VERSION 5.7 ;
BUSBITCHARS "[]" ;
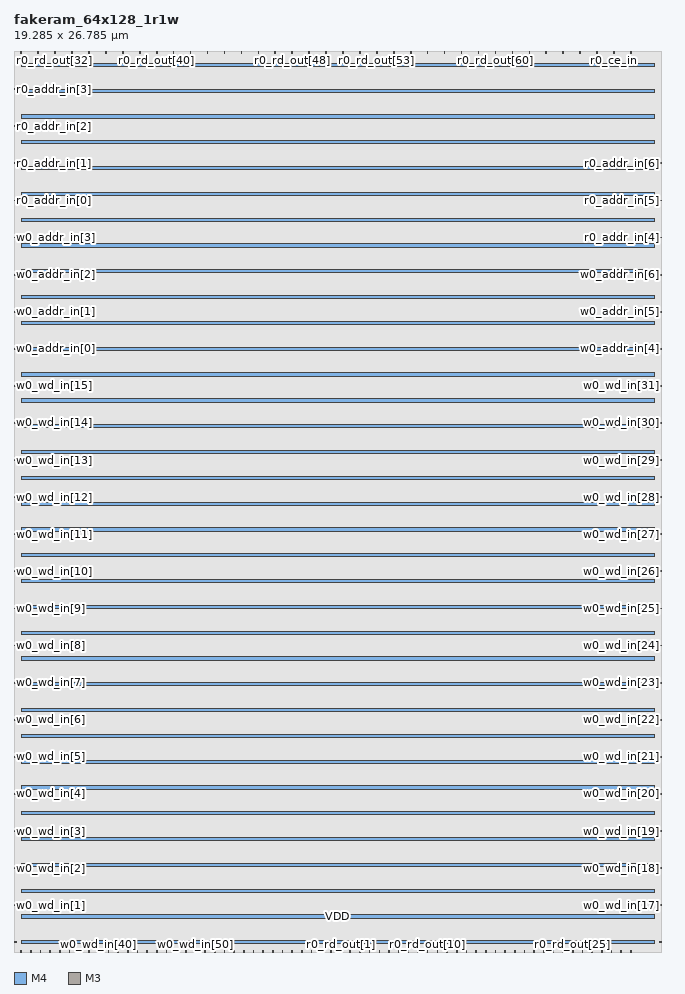
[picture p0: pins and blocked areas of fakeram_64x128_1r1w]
MACRO fakeram_64x128_1r1w
  FOREIGN fakeram_64x128_1r1w 0 0 ;
  SYMMETRY X Y R90 ;
  SIZE 19.285 BY 26.785 ;
  CLASS BLOCK ;
  PIN w0_wd_in[0]
    DIRECTION INPUT ;
    USE SIGNAL ;
    SHAPE ABUTMENT ;
    PORT
      LAYER M4 ;
      RECT 0.000 0.276 0.072 0.300 ;
    END
  END w0_wd_in[0]
  PIN w0_wd_in[1]
    DIRECTION INPUT ;
    USE SIGNAL ;
    SHAPE ABUTMENT ;
    PORT
      LAYER M4 ;
      RECT 0.000 1.380 0.072 1.404 ;
    END
  END w0_wd_in[1]
  PIN w0_wd_in[2]
    DIRECTION INPUT ;
    USE SIGNAL ;
    SHAPE ABUTMENT ;
    PORT
      LAYER M4 ;
      RECT 0.000 2.484 0.072 2.508 ;
    END
  END w0_wd_in[2]
  PIN w0_wd_in[3]
    DIRECTION INPUT ;
    USE SIGNAL ;
    SHAPE ABUTMENT ;
    PORT
      LAYER M4 ;
      RECT 0.000 3.588 0.072 3.612 ;
    END
  END w0_wd_in[3]
  PIN w0_wd_in[4]
    DIRECTION INPUT ;
    USE SIGNAL ;
    SHAPE ABUTMENT ;
    PORT
      LAYER M4 ;
      RECT 0.000 4.692 0.072 4.716 ;
    END
  END w0_wd_in[4]
  PIN w0_wd_in[5]
    DIRECTION INPUT ;
    USE SIGNAL ;
    SHAPE ABUTMENT ;
    PORT
      LAYER M4 ;
      RECT 0.000 5.796 0.072 5.820 ;
    END
  END w0_wd_in[5]
  PIN w0_wd_in[6]
    DIRECTION INPUT ;
    USE SIGNAL ;
    SHAPE ABUTMENT ;
    PORT
      LAYER M4 ;
      RECT 0.000 6.900 0.072 6.924 ;
    END
  END w0_wd_in[6]
  PIN w0_wd_in[7]
    DIRECTION INPUT ;
    USE SIGNAL ;
    SHAPE ABUTMENT ;
    PORT
      LAYER M4 ;
      RECT 0.000 8.004 0.072 8.028 ;
    END
  END w0_wd_in[7]
  PIN w0_wd_in[8]
    DIRECTION INPUT ;
    USE SIGNAL ;
    SHAPE ABUTMENT ;
    PORT
      LAYER M4 ;
      RECT 0.000 9.108 0.072 9.132 ;
    END
  END w0_wd_in[8]
  PIN w0_wd_in[9]
    DIRECTION INPUT ;
    USE SIGNAL ;
    SHAPE ABUTMENT ;
    PORT
      LAYER M4 ;
      RECT 0.000 10.212 0.072 10.236 ;
    END
  END w0_wd_in[9]
  PIN w0_wd_in[10]
    DIRECTION INPUT ;
    USE SIGNAL ;
    SHAPE ABUTMENT ;
    PORT
      LAYER M4 ;
      RECT 0.000 11.316 0.072 11.340 ;
    END
  END w0_wd_in[10]
  PIN w0_wd_in[11]
    DIRECTION INPUT ;
    USE SIGNAL ;
    SHAPE ABUTMENT ;
    PORT
      LAYER M4 ;
      RECT 0.000 12.420 0.072 12.444 ;
    END
  END w0_wd_in[11]
  PIN w0_wd_in[12]
    DIRECTION INPUT ;
    USE SIGNAL ;
    SHAPE ABUTMENT ;
    PORT
      LAYER M4 ;
      RECT 0.000 13.524 0.072 13.548 ;
    END
  END w0_wd_in[12]
  PIN w0_wd_in[13]
    DIRECTION INPUT ;
    USE SIGNAL ;
    SHAPE ABUTMENT ;
    PORT
      LAYER M4 ;
      RECT 0.000 14.628 0.072 14.652 ;
    END
  END w0_wd_in[13]
  PIN w0_wd_in[14]
    DIRECTION INPUT ;
    USE SIGNAL ;
    SHAPE ABUTMENT ;
    PORT
      LAYER M4 ;
      RECT 0.000 15.732 0.072 15.756 ;
    END
  END w0_wd_in[14]
  PIN w0_wd_in[15]
    DIRECTION INPUT ;
    USE SIGNAL ;
    SHAPE ABUTMENT ;
    PORT
      LAYER M4 ;
      RECT 0.000 16.836 0.072 16.860 ;
    END
  END w0_wd_in[15]
  PIN w0_wd_in[16]
    DIRECTION INPUT ;
    USE SIGNAL ;
    SHAPE ABUTMENT ;
    PORT
      LAYER M4 ;
      RECT 19.213 0.276 19.285 0.300 ;
    END
  END w0_wd_in[16]
  PIN w0_wd_in[17]
    DIRECTION INPUT ;
    USE SIGNAL ;
    SHAPE ABUTMENT ;
    PORT
      LAYER M4 ;
      RECT 19.213 1.380 19.285 1.404 ;
    END
  END w0_wd_in[17]
  PIN w0_wd_in[18]
    DIRECTION INPUT ;
    USE SIGNAL ;
    SHAPE ABUTMENT ;
    PORT
      LAYER M4 ;
      RECT 19.213 2.484 19.285 2.508 ;
    END
  END w0_wd_in[18]
  PIN w0_wd_in[19]
    DIRECTION INPUT ;
    USE SIGNAL ;
    SHAPE ABUTMENT ;
    PORT
      LAYER M4 ;
      RECT 19.213 3.588 19.285 3.612 ;
    END
  END w0_wd_in[19]
  PIN w0_wd_in[20]
    DIRECTION INPUT ;
    USE SIGNAL ;
    SHAPE ABUTMENT ;
    PORT
      LAYER M4 ;
      RECT 19.213 4.692 19.285 4.716 ;
    END
  END w0_wd_in[20]
  PIN w0_wd_in[21]
    DIRECTION INPUT ;
    USE SIGNAL ;
    SHAPE ABUTMENT ;
    PORT
      LAYER M4 ;
      RECT 19.213 5.796 19.285 5.820 ;
    END
  END w0_wd_in[21]
  PIN w0_wd_in[22]
    DIRECTION INPUT ;
    USE SIGNAL ;
    SHAPE ABUTMENT ;
    PORT
      LAYER M4 ;
      RECT 19.213 6.900 19.285 6.924 ;
    END
  END w0_wd_in[22]
  PIN w0_wd_in[23]
    DIRECTION INPUT ;
    USE SIGNAL ;
    SHAPE ABUTMENT ;
    PORT
      LAYER M4 ;
      RECT 19.213 8.004 19.285 8.028 ;
    END
  END w0_wd_in[23]
  PIN w0_wd_in[24]
    DIRECTION INPUT ;
    USE SIGNAL ;
    SHAPE ABUTMENT ;
    PORT
      LAYER M4 ;
      RECT 19.213 9.108 19.285 9.132 ;
    END
  END w0_wd_in[24]
  PIN w0_wd_in[25]
    DIRECTION INPUT ;
    USE SIGNAL ;
    SHAPE ABUTMENT ;
    PORT
      LAYER M4 ;
      RECT 19.213 10.212 19.285 10.236 ;
    END
  END w0_wd_in[25]
  PIN w0_wd_in[26]
    DIRECTION INPUT ;
    USE SIGNAL ;
    SHAPE ABUTMENT ;
    PORT
      LAYER M4 ;
      RECT 19.213 11.316 19.285 11.340 ;
    END
  END w0_wd_in[26]
  PIN w0_wd_in[27]
    DIRECTION INPUT ;
    USE SIGNAL ;
    SHAPE ABUTMENT ;
    PORT
      LAYER M4 ;
      RECT 19.213 12.420 19.285 12.444 ;
    END
  END w0_wd_in[27]
  PIN w0_wd_in[28]
    DIRECTION INPUT ;
    USE SIGNAL ;
    SHAPE ABUTMENT ;
    PORT
      LAYER M4 ;
      RECT 19.213 13.524 19.285 13.548 ;
    END
  END w0_wd_in[28]
  PIN w0_wd_in[29]
    DIRECTION INPUT ;
    USE SIGNAL ;
    SHAPE ABUTMENT ;
    PORT
      LAYER M4 ;
      RECT 19.213 14.628 19.285 14.652 ;
    END
  END w0_wd_in[29]
  PIN w0_wd_in[30]
    DIRECTION INPUT ;
    USE SIGNAL ;
    SHAPE ABUTMENT ;
    PORT
      LAYER M4 ;
      RECT 19.213 15.732 19.285 15.756 ;
    END
  END w0_wd_in[30]
  PIN w0_wd_in[31]
    DIRECTION INPUT ;
    USE SIGNAL ;
    SHAPE ABUTMENT ;
    PORT
      LAYER M4 ;
      RECT 19.213 16.836 19.285 16.860 ;
    END
  END w0_wd_in[31]
  PIN w0_wd_in[32]
    DIRECTION OUTPUT ;
    USE SIGNAL ;
    SHAPE ABUTMENT ;
    PORT
      LAYER M3 ;
      RECT 0.207 0.000 0.225 0.054 ;
    END
  END w0_wd_in[32]
  PIN w0_wd_in[33]
    DIRECTION OUTPUT ;
    USE SIGNAL ;
    SHAPE ABUTMENT ;
    PORT
      LAYER M3 ;
      RECT 0.495 0.000 0.513 0.054 ;
    END
  END w0_wd_in[33]
  PIN w0_wd_in[34]
    DIRECTION OUTPUT ;
    USE SIGNAL ;
    SHAPE ABUTMENT ;
    PORT
      LAYER M3 ;
      RECT 0.783 0.000 0.801 0.054 ;
    END
  END w0_wd_in[34]
  PIN w0_wd_in[35]
    DIRECTION OUTPUT ;
    USE SIGNAL ;
    SHAPE ABUTMENT ;
    PORT
      LAYER M3 ;
      RECT 1.071 0.000 1.089 0.054 ;
    END
  END w0_wd_in[35]
  PIN w0_wd_in[36]
    DIRECTION OUTPUT ;
    USE SIGNAL ;
    SHAPE ABUTMENT ;
    PORT
      LAYER M3 ;
      RECT 1.359 0.000 1.377 0.054 ;
    END
  END w0_wd_in[36]
  PIN w0_wd_in[37]
    DIRECTION OUTPUT ;
    USE SIGNAL ;
    SHAPE ABUTMENT ;
    PORT
      LAYER M3 ;
      RECT 1.647 0.000 1.665 0.054 ;
    END
  END w0_wd_in[37]
  PIN w0_wd_in[38]
    DIRECTION OUTPUT ;
    USE SIGNAL ;
    SHAPE ABUTMENT ;
    PORT
      LAYER M3 ;
      RECT 1.935 0.000 1.953 0.054 ;
    END
  END w0_wd_in[38]
  PIN w0_wd_in[39]
    DIRECTION OUTPUT ;
    USE SIGNAL ;
    SHAPE ABUTMENT ;
    PORT
      LAYER M3 ;
      RECT 2.223 0.000 2.241 0.054 ;
    END
  END w0_wd_in[39]
  PIN w0_wd_in[40]
    DIRECTION OUTPUT ;
    USE SIGNAL ;
    SHAPE ABUTMENT ;
    PORT
      LAYER M3 ;
      RECT 2.511 0.000 2.529 0.054 ;
    END
  END w0_wd_in[40]
  PIN w0_wd_in[41]
    DIRECTION OUTPUT ;
    USE SIGNAL ;
    SHAPE ABUTMENT ;
    PORT
      LAYER M3 ;
      RECT 2.799 0.000 2.817 0.054 ;
    END
  END w0_wd_in[41]
  PIN w0_wd_in[42]
    DIRECTION OUTPUT ;
    USE SIGNAL ;
    SHAPE ABUTMENT ;
    PORT
      LAYER M3 ;
      RECT 3.087 0.000 3.105 0.054 ;
    END
  END w0_wd_in[42]
  PIN w0_wd_in[43]
    DIRECTION OUTPUT ;
    USE SIGNAL ;
    SHAPE ABUTMENT ;
    PORT
      LAYER M3 ;
      RECT 3.375 0.000 3.393 0.054 ;
    END
  END w0_wd_in[43]
  PIN w0_wd_in[44]
    DIRECTION OUTPUT ;
    USE SIGNAL ;
    SHAPE ABUTMENT ;
    PORT
      LAYER M3 ;
      RECT 3.663 0.000 3.681 0.054 ;
    END
  END w0_wd_in[44]
  PIN w0_wd_in[45]
    DIRECTION OUTPUT ;
    USE SIGNAL ;
    SHAPE ABUTMENT ;
    PORT
      LAYER M3 ;
      RECT 3.951 0.000 3.969 0.054 ;
    END
  END w0_wd_in[45]
  PIN w0_wd_in[46]
    DIRECTION OUTPUT ;
    USE SIGNAL ;
    SHAPE ABUTMENT ;
    PORT
      LAYER M3 ;
      RECT 4.239 0.000 4.257 0.054 ;
    END
  END w0_wd_in[46]
  PIN w0_wd_in[47]
    DIRECTION OUTPUT ;
    USE SIGNAL ;
    SHAPE ABUTMENT ;
    PORT
      LAYER M3 ;
      RECT 4.527 0.000 4.545 0.054 ;
    END
  END w0_wd_in[47]
  PIN w0_wd_in[48]
    DIRECTION OUTPUT ;
    USE SIGNAL ;
    SHAPE ABUTMENT ;
    PORT
      LAYER M3 ;
      RECT 4.815 0.000 4.833 0.054 ;
    END
  END w0_wd_in[48]
  PIN w0_wd_in[49]
    DIRECTION OUTPUT ;
    USE SIGNAL ;
    SHAPE ABUTMENT ;
    PORT
      LAYER M3 ;
      RECT 5.103 0.000 5.121 0.054 ;
    END
  END w0_wd_in[49]
  PIN w0_wd_in[50]
    DIRECTION OUTPUT ;
    USE SIGNAL ;
    SHAPE ABUTMENT ;
    PORT
      LAYER M3 ;
      RECT 5.391 0.000 5.409 0.054 ;
    END
  END w0_wd_in[50]
  PIN w0_wd_in[51]
    DIRECTION OUTPUT ;
    USE SIGNAL ;
    SHAPE ABUTMENT ;
    PORT
      LAYER M3 ;
      RECT 5.679 0.000 5.697 0.054 ;
    END
  END w0_wd_in[51]
  PIN w0_wd_in[52]
    DIRECTION OUTPUT ;
    USE SIGNAL ;
    SHAPE ABUTMENT ;
    PORT
      LAYER M3 ;
      RECT 5.967 0.000 5.985 0.054 ;
    END
  END w0_wd_in[52]
  PIN w0_wd_in[53]
    DIRECTION OUTPUT ;
    USE SIGNAL ;
    SHAPE ABUTMENT ;
    PORT
      LAYER M3 ;
      RECT 6.255 0.000 6.273 0.054 ;
    END
  END w0_wd_in[53]
  PIN w0_wd_in[54]
    DIRECTION OUTPUT ;
    USE SIGNAL ;
    SHAPE ABUTMENT ;
    PORT
      LAYER M3 ;
      RECT 6.543 0.000 6.561 0.054 ;
    END
  END w0_wd_in[54]
  PIN w0_wd_in[55]
    DIRECTION OUTPUT ;
    USE SIGNAL ;
    SHAPE ABUTMENT ;
    PORT
      LAYER M3 ;
      RECT 6.831 0.000 6.849 0.054 ;
    END
  END w0_wd_in[55]
  PIN w0_wd_in[56]
    DIRECTION OUTPUT ;
    USE SIGNAL ;
    SHAPE ABUTMENT ;
    PORT
      LAYER M3 ;
      RECT 7.119 0.000 7.137 0.054 ;
    END
  END w0_wd_in[56]
  PIN w0_wd_in[57]
    DIRECTION OUTPUT ;
    USE SIGNAL ;
    SHAPE ABUTMENT ;
    PORT
      LAYER M3 ;
      RECT 7.407 0.000 7.425 0.054 ;
    END
  END w0_wd_in[57]
  PIN w0_wd_in[58]
    DIRECTION OUTPUT ;
    USE SIGNAL ;
    SHAPE ABUTMENT ;
    PORT
      LAYER M3 ;
      RECT 7.695 0.000 7.713 0.054 ;
    END
  END w0_wd_in[58]
  PIN w0_wd_in[59]
    DIRECTION OUTPUT ;
    USE SIGNAL ;
    SHAPE ABUTMENT ;
    PORT
      LAYER M3 ;
      RECT 7.983 0.000 8.001 0.054 ;
    END
  END w0_wd_in[59]
  PIN w0_wd_in[60]
    DIRECTION OUTPUT ;
    USE SIGNAL ;
    SHAPE ABUTMENT ;
    PORT
      LAYER M3 ;
      RECT 8.271 0.000 8.289 0.054 ;
    END
  END w0_wd_in[60]
  PIN w0_wd_in[61]
    DIRECTION OUTPUT ;
    USE SIGNAL ;
    SHAPE ABUTMENT ;
    PORT
      LAYER M3 ;
      RECT 8.559 0.000 8.577 0.054 ;
    END
  END w0_wd_in[61]
  PIN w0_wd_in[62]
    DIRECTION OUTPUT ;
    USE SIGNAL ;
    SHAPE ABUTMENT ;
    PORT
      LAYER M3 ;
      RECT 8.847 0.000 8.865 0.054 ;
    END
  END w0_wd_in[62]
  PIN w0_wd_in[63]
    DIRECTION OUTPUT ;
    USE SIGNAL ;
    SHAPE ABUTMENT ;
    PORT
      LAYER M3 ;
      RECT 9.135 0.000 9.153 0.054 ;
    END
  END w0_wd_in[63]
  PIN r0_rd_out[0]
    DIRECTION OUTPUT ;
    USE SIGNAL ;
    SHAPE ABUTMENT ;
    PORT
      LAYER M3 ;
      RECT 9.423 0.000 9.441 0.054 ;
    END
  END r0_rd_out[0]
  PIN r0_rd_out[1]
    DIRECTION OUTPUT ;
    USE SIGNAL ;
    SHAPE ABUTMENT ;
    PORT
      LAYER M3 ;
      RECT 9.711 0.000 9.729 0.054 ;
    END
  END r0_rd_out[1]
  PIN r0_rd_out[2]
    DIRECTION OUTPUT ;
    USE SIGNAL ;
    SHAPE ABUTMENT ;
    PORT
      LAYER M3 ;
      RECT 9.999 0.000 10.017 0.054 ;
    END
  END r0_rd_out[2]
  PIN r0_rd_out[3]
    DIRECTION OUTPUT ;
    USE SIGNAL ;
    SHAPE ABUTMENT ;
    PORT
      LAYER M3 ;
      RECT 10.287 0.000 10.305 0.054 ;
    END
  END r0_rd_out[3]
  PIN r0_rd_out[4]
    DIRECTION OUTPUT ;
    USE SIGNAL ;
    SHAPE ABUTMENT ;
    PORT
      LAYER M3 ;
      RECT 10.575 0.000 10.593 0.054 ;
    END
  END r0_rd_out[4]
  PIN r0_rd_out[5]
    DIRECTION OUTPUT ;
    USE SIGNAL ;
    SHAPE ABUTMENT ;
    PORT
      LAYER M3 ;
      RECT 10.863 0.000 10.881 0.054 ;
    END
  END r0_rd_out[5]
  PIN r0_rd_out[6]
    DIRECTION OUTPUT ;
    USE SIGNAL ;
    SHAPE ABUTMENT ;
    PORT
      LAYER M3 ;
      RECT 11.151 0.000 11.169 0.054 ;
    END
  END r0_rd_out[6]
  PIN r0_rd_out[7]
    DIRECTION OUTPUT ;
    USE SIGNAL ;
    SHAPE ABUTMENT ;
    PORT
      LAYER M3 ;
      RECT 11.439 0.000 11.457 0.054 ;
    END
  END r0_rd_out[7]
  PIN r0_rd_out[8]
    DIRECTION OUTPUT ;
    USE SIGNAL ;
    SHAPE ABUTMENT ;
    PORT
      LAYER M3 ;
      RECT 11.727 0.000 11.745 0.054 ;
    END
  END r0_rd_out[8]
  PIN r0_rd_out[9]
    DIRECTION OUTPUT ;
    USE SIGNAL ;
    SHAPE ABUTMENT ;
    PORT
      LAYER M3 ;
      RECT 12.015 0.000 12.033 0.054 ;
    END
  END r0_rd_out[9]
  PIN r0_rd_out[10]
    DIRECTION OUTPUT ;
    USE SIGNAL ;
    SHAPE ABUTMENT ;
    PORT
      LAYER M3 ;
      RECT 12.303 0.000 12.321 0.054 ;
    END
  END r0_rd_out[10]
  PIN r0_rd_out[11]
    DIRECTION OUTPUT ;
    USE SIGNAL ;
    SHAPE ABUTMENT ;
    PORT
      LAYER M3 ;
      RECT 12.591 0.000 12.609 0.054 ;
    END
  END r0_rd_out[11]
  PIN r0_rd_out[12]
    DIRECTION OUTPUT ;
    USE SIGNAL ;
    SHAPE ABUTMENT ;
    PORT
      LAYER M3 ;
      RECT 12.879 0.000 12.897 0.054 ;
    END
  END r0_rd_out[12]
  PIN r0_rd_out[13]
    DIRECTION OUTPUT ;
    USE SIGNAL ;
    SHAPE ABUTMENT ;
    PORT
      LAYER M3 ;
      RECT 13.167 0.000 13.185 0.054 ;
    END
  END r0_rd_out[13]
  PIN r0_rd_out[14]
    DIRECTION OUTPUT ;
    USE SIGNAL ;
    SHAPE ABUTMENT ;
    PORT
      LAYER M3 ;
      RECT 13.455 0.000 13.473 0.054 ;
    END
  END r0_rd_out[14]
  PIN r0_rd_out[15]
    DIRECTION OUTPUT ;
    USE SIGNAL ;
    SHAPE ABUTMENT ;
    PORT
      LAYER M3 ;
      RECT 13.743 0.000 13.761 0.054 ;
    END
  END r0_rd_out[15]
  PIN r0_rd_out[16]
    DIRECTION OUTPUT ;
    USE SIGNAL ;
    SHAPE ABUTMENT ;
    PORT
      LAYER M3 ;
      RECT 14.031 0.000 14.049 0.054 ;
    END
  END r0_rd_out[16]
  PIN r0_rd_out[17]
    DIRECTION OUTPUT ;
    USE SIGNAL ;
    SHAPE ABUTMENT ;
    PORT
      LAYER M3 ;
      RECT 14.319 0.000 14.337 0.054 ;
    END
  END r0_rd_out[17]
  PIN r0_rd_out[18]
    DIRECTION OUTPUT ;
    USE SIGNAL ;
    SHAPE ABUTMENT ;
    PORT
      LAYER M3 ;
      RECT 14.607 0.000 14.625 0.054 ;
    END
  END r0_rd_out[18]
  PIN r0_rd_out[19]
    DIRECTION OUTPUT ;
    USE SIGNAL ;
    SHAPE ABUTMENT ;
    PORT
      LAYER M3 ;
      RECT 14.895 0.000 14.913 0.054 ;
    END
  END r0_rd_out[19]
  PIN r0_rd_out[20]
    DIRECTION OUTPUT ;
    USE SIGNAL ;
    SHAPE ABUTMENT ;
    PORT
      LAYER M3 ;
      RECT 15.183 0.000 15.201 0.054 ;
    END
  END r0_rd_out[20]
  PIN r0_rd_out[21]
    DIRECTION OUTPUT ;
    USE SIGNAL ;
    SHAPE ABUTMENT ;
    PORT
      LAYER M3 ;
      RECT 15.471 0.000 15.489 0.054 ;
    END
  END r0_rd_out[21]
  PIN r0_rd_out[22]
    DIRECTION OUTPUT ;
    USE SIGNAL ;
    SHAPE ABUTMENT ;
    PORT
      LAYER M3 ;
      RECT 15.759 0.000 15.777 0.054 ;
    END
  END r0_rd_out[22]
  PIN r0_rd_out[23]
    DIRECTION OUTPUT ;
    USE SIGNAL ;
    SHAPE ABUTMENT ;
    PORT
      LAYER M3 ;
      RECT 16.047 0.000 16.065 0.054 ;
    END
  END r0_rd_out[23]
  PIN r0_rd_out[24]
    DIRECTION OUTPUT ;
    USE SIGNAL ;
    SHAPE ABUTMENT ;
    PORT
      LAYER M3 ;
      RECT 16.335 0.000 16.353 0.054 ;
    END
  END r0_rd_out[24]
  PIN r0_rd_out[25]
    DIRECTION OUTPUT ;
    USE SIGNAL ;
    SHAPE ABUTMENT ;
    PORT
      LAYER M3 ;
      RECT 16.623 0.000 16.641 0.054 ;
    END
  END r0_rd_out[25]
  PIN r0_rd_out[26]
    DIRECTION OUTPUT ;
    USE SIGNAL ;
    SHAPE ABUTMENT ;
    PORT
      LAYER M3 ;
      RECT 16.911 0.000 16.929 0.054 ;
    END
  END r0_rd_out[26]
  PIN r0_rd_out[27]
    DIRECTION OUTPUT ;
    USE SIGNAL ;
    SHAPE ABUTMENT ;
    PORT
      LAYER M3 ;
      RECT 17.199 0.000 17.217 0.054 ;
    END
  END r0_rd_out[27]
  PIN r0_rd_out[28]
    DIRECTION OUTPUT ;
    USE SIGNAL ;
    SHAPE ABUTMENT ;
    PORT
      LAYER M3 ;
      RECT 17.487 0.000 17.505 0.054 ;
    END
  END r0_rd_out[28]
  PIN r0_rd_out[29]
    DIRECTION OUTPUT ;
    USE SIGNAL ;
    SHAPE ABUTMENT ;
    PORT
      LAYER M3 ;
      RECT 17.775 0.000 17.793 0.054 ;
    END
  END r0_rd_out[29]
  PIN r0_rd_out[30]
    DIRECTION OUTPUT ;
    USE SIGNAL ;
    SHAPE ABUTMENT ;
    PORT
      LAYER M3 ;
      RECT 18.063 0.000 18.081 0.054 ;
    END
  END r0_rd_out[30]
  PIN r0_rd_out[31]
    DIRECTION OUTPUT ;
    USE SIGNAL ;
    SHAPE ABUTMENT ;
    PORT
      LAYER M3 ;
      RECT 18.351 0.000 18.369 0.054 ;
    END
  END r0_rd_out[31]
  PIN r0_rd_out[32]
    DIRECTION OUTPUT ;
    USE SIGNAL ;
    SHAPE ABUTMENT ;
    PORT
      LAYER M3 ;
      RECT 0.207 26.731 0.225 26.785 ;
    END
  END r0_rd_out[32]
  PIN r0_rd_out[33]
    DIRECTION OUTPUT ;
    USE SIGNAL ;
    SHAPE ABUTMENT ;
    PORT
      LAYER M3 ;
      RECT 0.711 26.731 0.729 26.785 ;
    END
  END r0_rd_out[33]
  PIN r0_rd_out[34]
    DIRECTION OUTPUT ;
    USE SIGNAL ;
    SHAPE ABUTMENT ;
    PORT
      LAYER M3 ;
      RECT 1.215 26.731 1.233 26.785 ;
    END
  END r0_rd_out[34]
  PIN r0_rd_out[35]
    DIRECTION OUTPUT ;
    USE SIGNAL ;
    SHAPE ABUTMENT ;
    PORT
      LAYER M3 ;
      RECT 1.719 26.731 1.737 26.785 ;
    END
  END r0_rd_out[35]
  PIN r0_rd_out[36]
    DIRECTION OUTPUT ;
    USE SIGNAL ;
    SHAPE ABUTMENT ;
    PORT
      LAYER M3 ;
      RECT 2.223 26.731 2.241 26.785 ;
    END
  END r0_rd_out[36]
  PIN r0_rd_out[37]
    DIRECTION OUTPUT ;
    USE SIGNAL ;
    SHAPE ABUTMENT ;
    PORT
      LAYER M3 ;
      RECT 2.727 26.731 2.745 26.785 ;
    END
  END r0_rd_out[37]
  PIN r0_rd_out[38]
    DIRECTION OUTPUT ;
    USE SIGNAL ;
    SHAPE ABUTMENT ;
    PORT
      LAYER M3 ;
      RECT 3.231 26.731 3.249 26.785 ;
    END
  END r0_rd_out[38]
  PIN r0_rd_out[39]
    DIRECTION OUTPUT ;
    USE SIGNAL ;
    SHAPE ABUTMENT ;
    PORT
      LAYER M3 ;
      RECT 3.735 26.731 3.753 26.785 ;
    END
  END r0_rd_out[39]
  PIN r0_rd_out[40]
    DIRECTION OUTPUT ;
    USE SIGNAL ;
    SHAPE ABUTMENT ;
    PORT
      LAYER M3 ;
      RECT 4.239 26.731 4.257 26.785 ;
    END
  END r0_rd_out[40]
  PIN r0_rd_out[41]
    DIRECTION OUTPUT ;
    USE SIGNAL ;
    SHAPE ABUTMENT ;
    PORT
      LAYER M3 ;
      RECT 4.743 26.731 4.761 26.785 ;
    END
  END r0_rd_out[41]
  PIN r0_rd_out[42]
    DIRECTION OUTPUT ;
    USE SIGNAL ;
    SHAPE ABUTMENT ;
    PORT
      LAYER M3 ;
      RECT 5.247 26.731 5.265 26.785 ;
    END
  END r0_rd_out[42]
  PIN r0_rd_out[43]
    DIRECTION OUTPUT ;
    USE SIGNAL ;
    SHAPE ABUTMENT ;
    PORT
      LAYER M3 ;
      RECT 5.751 26.731 5.769 26.785 ;
    END
  END r0_rd_out[43]
  PIN r0_rd_out[44]
    DIRECTION OUTPUT ;
    USE SIGNAL ;
    SHAPE ABUTMENT ;
    PORT
      LAYER M3 ;
      RECT 6.255 26.731 6.273 26.785 ;
    END
  END r0_rd_out[44]
  PIN r0_rd_out[45]
    DIRECTION OUTPUT ;
    USE SIGNAL ;
    SHAPE ABUTMENT ;
    PORT
      LAYER M3 ;
      RECT 6.759 26.731 6.777 26.785 ;
    END
  END r0_rd_out[45]
  PIN r0_rd_out[46]
    DIRECTION OUTPUT ;
    USE SIGNAL ;
    SHAPE ABUTMENT ;
    PORT
      LAYER M3 ;
      RECT 7.263 26.731 7.281 26.785 ;
    END
  END r0_rd_out[46]
  PIN r0_rd_out[47]
    DIRECTION OUTPUT ;
    USE SIGNAL ;
    SHAPE ABUTMENT ;
    PORT
      LAYER M3 ;
      RECT 7.767 26.731 7.785 26.785 ;
    END
  END r0_rd_out[47]
  PIN r0_rd_out[48]
    DIRECTION OUTPUT ;
    USE SIGNAL ;
    SHAPE ABUTMENT ;
    PORT
      LAYER M3 ;
      RECT 8.271 26.731 8.289 26.785 ;
    END
  END r0_rd_out[48]
  PIN r0_rd_out[49]
    DIRECTION OUTPUT ;
    USE SIGNAL ;
    SHAPE ABUTMENT ;
    PORT
      LAYER M3 ;
      RECT 8.775 26.731 8.793 26.785 ;
    END
  END r0_rd_out[49]
  PIN r0_rd_out[50]
    DIRECTION OUTPUT ;
    USE SIGNAL ;
    SHAPE ABUTMENT ;
    PORT
      LAYER M3 ;
      RECT 9.279 26.731 9.297 26.785 ;
    END
  END r0_rd_out[50]
  PIN r0_rd_out[51]
    DIRECTION OUTPUT ;
    USE SIGNAL ;
    SHAPE ABUTMENT ;
    PORT
      LAYER M3 ;
      RECT 9.783 26.731 9.801 26.785 ;
    END
  END r0_rd_out[51]
  PIN r0_rd_out[52]
    DIRECTION OUTPUT ;
    USE SIGNAL ;
    SHAPE ABUTMENT ;
    PORT
      LAYER M3 ;
      RECT 10.287 26.731 10.305 26.785 ;
    END
  END r0_rd_out[52]
  PIN r0_rd_out[53]
    DIRECTION OUTPUT ;
    USE SIGNAL ;
    SHAPE ABUTMENT ;
    PORT
      LAYER M3 ;
      RECT 10.791 26.731 10.809 26.785 ;
    END
  END r0_rd_out[53]
  PIN r0_rd_out[54]
    DIRECTION OUTPUT ;
    USE SIGNAL ;
    SHAPE ABUTMENT ;
    PORT
      LAYER M3 ;
      RECT 11.295 26.731 11.313 26.785 ;
    END
  END r0_rd_out[54]
  PIN r0_rd_out[55]
    DIRECTION OUTPUT ;
    USE SIGNAL ;
    SHAPE ABUTMENT ;
    PORT
      LAYER M3 ;
      RECT 11.799 26.731 11.817 26.785 ;
    END
  END r0_rd_out[55]
  PIN r0_rd_out[56]
    DIRECTION OUTPUT ;
    USE SIGNAL ;
    SHAPE ABUTMENT ;
    PORT
      LAYER M3 ;
      RECT 12.303 26.731 12.321 26.785 ;
    END
  END r0_rd_out[56]
  PIN r0_rd_out[57]
    DIRECTION OUTPUT ;
    USE SIGNAL ;
    SHAPE ABUTMENT ;
    PORT
      LAYER M3 ;
      RECT 12.807 26.731 12.825 26.785 ;
    END
  END r0_rd_out[57]
  PIN r0_rd_out[58]
    DIRECTION OUTPUT ;
    USE SIGNAL ;
    SHAPE ABUTMENT ;
    PORT
      LAYER M3 ;
      RECT 13.311 26.731 13.329 26.785 ;
    END
  END r0_rd_out[58]
  PIN r0_rd_out[59]
    DIRECTION OUTPUT ;
    USE SIGNAL ;
    SHAPE ABUTMENT ;
    PORT
      LAYER M3 ;
      RECT 13.815 26.731 13.833 26.785 ;
    END
  END r0_rd_out[59]
  PIN r0_rd_out[60]
    DIRECTION OUTPUT ;
    USE SIGNAL ;
    SHAPE ABUTMENT ;
    PORT
      LAYER M3 ;
      RECT 14.319 26.731 14.337 26.785 ;
    END
  END r0_rd_out[60]
  PIN r0_rd_out[61]
    DIRECTION OUTPUT ;
    USE SIGNAL ;
    SHAPE ABUTMENT ;
    PORT
      LAYER M3 ;
      RECT 14.823 26.731 14.841 26.785 ;
    END
  END r0_rd_out[61]
  PIN r0_rd_out[62]
    DIRECTION OUTPUT ;
    USE SIGNAL ;
    SHAPE ABUTMENT ;
    PORT
      LAYER M3 ;
      RECT 15.327 26.731 15.345 26.785 ;
    END
  END r0_rd_out[62]
  PIN r0_rd_out[63]
    DIRECTION OUTPUT ;
    USE SIGNAL ;
    SHAPE ABUTMENT ;
    PORT
      LAYER M3 ;
      RECT 15.831 26.731 15.849 26.785 ;
    END
  END r0_rd_out[63]
  PIN w0_addr_in[0]
    DIRECTION INPUT ;
    USE SIGNAL ;
    SHAPE ABUTMENT ;
    PORT
      LAYER M4 ;
      RECT 0.000 17.940 0.072 17.964 ;
    END
  END w0_addr_in[0]
  PIN w0_addr_in[1]
    DIRECTION INPUT ;
    USE SIGNAL ;
    SHAPE ABUTMENT ;
    PORT
      LAYER M4 ;
      RECT 0.000 19.044 0.072 19.068 ;
    END
  END w0_addr_in[1]
  PIN w0_addr_in[2]
    DIRECTION INPUT ;
    USE SIGNAL ;
    SHAPE ABUTMENT ;
    PORT
      LAYER M4 ;
      RECT 0.000 20.148 0.072 20.172 ;
    END
  END w0_addr_in[2]
  PIN w0_addr_in[3]
    DIRECTION INPUT ;
    USE SIGNAL ;
    SHAPE ABUTMENT ;
    PORT
      LAYER M4 ;
      RECT 0.000 21.252 0.072 21.276 ;
    END
  END w0_addr_in[3]
  PIN w0_addr_in[4]
    DIRECTION INPUT ;
    USE SIGNAL ;
    SHAPE ABUTMENT ;
    PORT
      LAYER M4 ;
      RECT 19.213 17.940 19.285 17.964 ;
    END
  END w0_addr_in[4]
  PIN w0_addr_in[5]
    DIRECTION INPUT ;
    USE SIGNAL ;
    SHAPE ABUTMENT ;
    PORT
      LAYER M4 ;
      RECT 19.213 19.044 19.285 19.068 ;
    END
  END w0_addr_in[5]
  PIN w0_addr_in[6]
    DIRECTION INPUT ;
    USE SIGNAL ;
    SHAPE ABUTMENT ;
    PORT
      LAYER M4 ;
      RECT 19.213 20.148 19.285 20.172 ;
    END
  END w0_addr_in[6]
  PIN r0_addr_in[0]
    DIRECTION INPUT ;
    USE SIGNAL ;
    SHAPE ABUTMENT ;
    PORT
      LAYER M4 ;
      RECT 0.000 22.356 0.072 22.380 ;
    END
  END r0_addr_in[0]
  PIN r0_addr_in[1]
    DIRECTION INPUT ;
    USE SIGNAL ;
    SHAPE ABUTMENT ;
    PORT
      LAYER M4 ;
      RECT 0.000 23.460 0.072 23.484 ;
    END
  END r0_addr_in[1]
  PIN r0_addr_in[2]
    DIRECTION INPUT ;
    USE SIGNAL ;
    SHAPE ABUTMENT ;
    PORT
      LAYER M4 ;
      RECT 0.000 24.564 0.072 24.588 ;
    END
  END r0_addr_in[2]
  PIN r0_addr_in[3]
    DIRECTION INPUT ;
    USE SIGNAL ;
    SHAPE ABUTMENT ;
    PORT
      LAYER M4 ;
      RECT 0.000 25.668 0.072 25.692 ;
    END
  END r0_addr_in[3]
  PIN r0_addr_in[4]
    DIRECTION INPUT ;
    USE SIGNAL ;
    SHAPE ABUTMENT ;
    PORT
      LAYER M4 ;
      RECT 19.213 21.252 19.285 21.276 ;
    END
  END r0_addr_in[4]
  PIN r0_addr_in[5]
    DIRECTION INPUT ;
    USE SIGNAL ;
    SHAPE ABUTMENT ;
    PORT
      LAYER M4 ;
      RECT 19.213 22.356 19.285 22.380 ;
    END
  END r0_addr_in[5]
  PIN r0_addr_in[6]
    DIRECTION INPUT ;
    USE SIGNAL ;
    SHAPE ABUTMENT ;
    PORT
      LAYER M4 ;
      RECT 19.213 23.460 19.285 23.484 ;
    END
  END r0_addr_in[6]
  PIN w0_we_in
    DIRECTION INPUT ;
    USE SIGNAL ;
    SHAPE ABUTMENT ;
    PORT
      LAYER M3 ;
      RECT 16.335 26.731 16.353 26.785 ;
    END
  END w0_we_in
  PIN w0_ce_in
    DIRECTION INPUT ;
    USE SIGNAL ;
    SHAPE ABUTMENT ;
    PORT
      LAYER M3 ;
      RECT 16.839 26.731 16.857 26.785 ;
    END
  END w0_ce_in
  PIN w0_clk
    DIRECTION INPUT ;
    USE SIGNAL ;
    SHAPE ABUTMENT ;
    PORT
      LAYER M3 ;
      RECT 17.343 26.731 17.361 26.785 ;
    END
  END w0_clk
  PIN r0_ce_in
    DIRECTION INPUT ;
    USE SIGNAL ;
    SHAPE ABUTMENT ;
    PORT
      LAYER M3 ;
      RECT 17.847 26.731 17.865 26.785 ;
    END
  END r0_ce_in
  PIN r0_clk
    DIRECTION INPUT ;
    USE SIGNAL ;
    SHAPE ABUTMENT ;
    PORT
      LAYER M3 ;
      RECT 18.351 26.731 18.369 26.785 ;
    END
  END r0_clk
  PIN VSS
    DIRECTION INOUT ;
    USE GROUND ;
    PORT
      LAYER M4 ;
      RECT 0.216 0.240 19.069 0.336 ;
      RECT 0.216 1.008 19.069 1.104 ;
      RECT 0.216 1.776 19.069 1.872 ;
      RECT 0.216 2.544 19.069 2.640 ;
      RECT 0.216 3.312 19.069 3.408 ;
      RECT 0.216 4.080 19.069 4.176 ;
      RECT 0.216 4.848 19.069 4.944 ;
      RECT 0.216 5.616 19.069 5.712 ;
      RECT 0.216 6.384 19.069 6.480 ;
      RECT 0.216 7.152 19.069 7.248 ;
      RECT 0.216 7.920 19.069 8.016 ;
      RECT 0.216 8.688 19.069 8.784 ;
      RECT 0.216 9.456 19.069 9.552 ;
      RECT 0.216 10.224 19.069 10.320 ;
      RECT 0.216 10.992 19.069 11.088 ;
      RECT 0.216 11.760 19.069 11.856 ;
      RECT 0.216 12.528 19.069 12.624 ;
      RECT 0.216 13.296 19.069 13.392 ;
      RECT 0.216 14.064 19.069 14.160 ;
      RECT 0.216 14.832 19.069 14.928 ;
      RECT 0.216 15.600 19.069 15.696 ;
      RECT 0.216 16.368 19.069 16.464 ;
      RECT 0.216 17.136 19.069 17.232 ;
      RECT 0.216 17.904 19.069 18.000 ;
      RECT 0.216 18.672 19.069 18.768 ;
      RECT 0.216 19.440 19.069 19.536 ;
      RECT 0.216 20.208 19.069 20.304 ;
      RECT 0.216 20.976 19.069 21.072 ;
      RECT 0.216 21.744 19.069 21.840 ;
      RECT 0.216 22.512 19.069 22.608 ;
      RECT 0.216 23.280 19.069 23.376 ;
      RECT 0.216 24.048 19.069 24.144 ;
      RECT 0.216 24.816 19.069 24.912 ;
      RECT 0.216 25.584 19.069 25.680 ;
      RECT 0.216 26.352 19.069 26.448 ;
    END
  END VSS
  PIN VDD
    DIRECTION INOUT ;
    USE POWER ;
    PORT
      LAYER M4 ;
      RECT 0.216 0.240 19.069 0.336 ;
      RECT 0.216 1.008 19.069 1.104 ;
      RECT 0.216 1.776 19.069 1.872 ;
      RECT 0.216 2.544 19.069 2.640 ;
      RECT 0.216 3.312 19.069 3.408 ;
      RECT 0.216 4.080 19.069 4.176 ;
      RECT 0.216 4.848 19.069 4.944 ;
      RECT 0.216 5.616 19.069 5.712 ;
      RECT 0.216 6.384 19.069 6.480 ;
      RECT 0.216 7.152 19.069 7.248 ;
      RECT 0.216 7.920 19.069 8.016 ;
      RECT 0.216 8.688 19.069 8.784 ;
      RECT 0.216 9.456 19.069 9.552 ;
      RECT 0.216 10.224 19.069 10.320 ;
      RECT 0.216 10.992 19.069 11.088 ;
      RECT 0.216 11.760 19.069 11.856 ;
      RECT 0.216 12.528 19.069 12.624 ;
      RECT 0.216 13.296 19.069 13.392 ;
      RECT 0.216 14.064 19.069 14.160 ;
      RECT 0.216 14.832 19.069 14.928 ;
      RECT 0.216 15.600 19.069 15.696 ;
      RECT 0.216 16.368 19.069 16.464 ;
      RECT 0.216 17.136 19.069 17.232 ;
      RECT 0.216 17.904 19.069 18.000 ;
      RECT 0.216 18.672 19.069 18.768 ;
      RECT 0.216 19.440 19.069 19.536 ;
      RECT 0.216 20.208 19.069 20.304 ;
      RECT 0.216 20.976 19.069 21.072 ;
      RECT 0.216 21.744 19.069 21.840 ;
      RECT 0.216 22.512 19.069 22.608 ;
      RECT 0.216 23.280 19.069 23.376 ;
      RECT 0.216 24.048 19.069 24.144 ;
      RECT 0.216 24.816 19.069 24.912 ;
      RECT 0.216 25.584 19.069 25.680 ;
      RECT 0.216 26.352 19.069 26.448 ;
    END
  END VDD
  OBS
    LAYER M1 ;
    RECT 0 0 19.285 26.785 ;
    LAYER M2 ;
    RECT 0 0 19.285 26.785 ;
    LAYER M3 ;
    RECT 0 0 19.285 26.785 ;
    LAYER M4 ;
    RECT 0 0 19.285 26.785 ;
  END
END fakeram_64x128_1r1w

END LIBRARY
